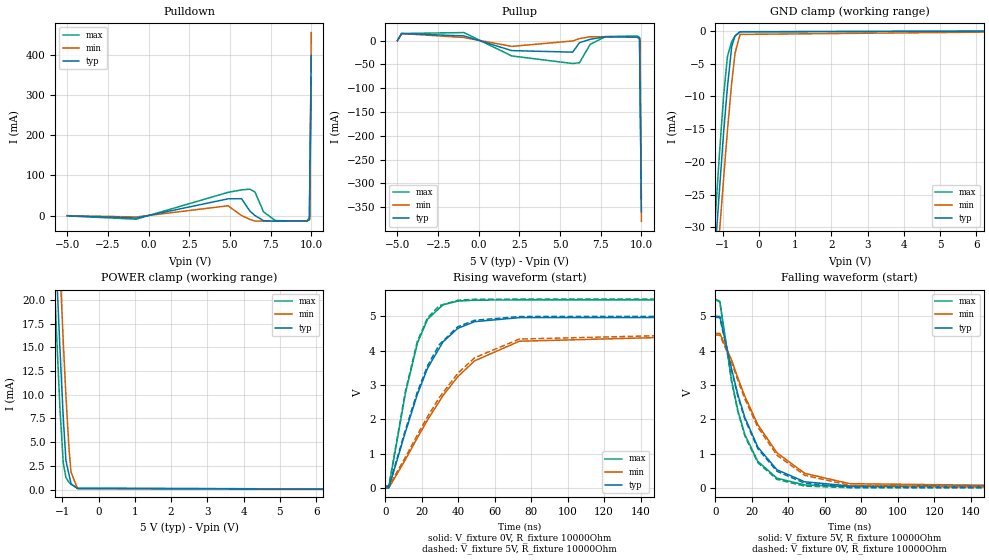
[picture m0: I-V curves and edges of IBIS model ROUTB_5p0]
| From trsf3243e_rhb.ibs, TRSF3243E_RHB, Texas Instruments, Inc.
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[Model]   ROUTB_5p0
Model_type   3-state
Polarity   Inverting
Vmeas = 2.5
Vref = 0
Cref = 150pF
Rref = 3000
|variable   typ   min   max
C_comp   1.38pF   1.30pF   1.43pF
|C_pullup   1.31pF   1.23pF   1.37pF
|C_pulldown   1.78pF   1.74pF   1.85pF
[Voltage Range]   5   4.5   5.5
[Temperature Range]   27   110   -40
[Pullup Reference]   5   4.5   5.5
[Pulldown Reference]   0   0   0
[Power Clamp Reference]   5   4.5   5.5
[GND Clamp Reference]   0   0   0
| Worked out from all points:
|   slope of the pulldown table from 0 to 0.75 V, typ, clamps not added: 91.3 ohm
|   slope of the pullup table from 0 to 0.75 V, typ, clamps not added: 81.9 ohm
|   GND clamp passes 1 mA (typ) near -0.68 V on its own axis
|   POWER clamp passes 1 mA (typ) near -0.78 V on its own axis
|   falling waveform, V_fixture 5V, R_fixture 10000Ohm: 20-80 % time 18.4ns typ, 25.7ns min, 14.3ns max; typ from 5 V to 0.039 V
|   rising waveform, V_fixture 0V, R_fixture 10000Ohm: 20-80 % time 20.4ns typ, 34.1ns min, 13.2ns max; typ from 0 V to 4.97 V
|   rising waveform, V_fixture 5V, R_fixture 10000Ohm: 20-80 % time 20.1ns typ, 33.3ns min, 13.1ns max; typ from 0.039 V to 5 V
|   falling waveform, V_fixture 0V, R_fixture 10000Ohm: 20-80 % time 18.3ns typ, 25.4ns min, 14.3ns max; typ from 4.97 V to 0 V
[Pulldown]
|   Voltage   I(typ)   I(min)   I(max)
-5V       -780.8uA   -278.4uA   -898.2uA
-764.5mV  -6.348mA   -3.623mA   -9.147mA
4.882V    41.67mA    24.34mA    57.85mA
5.716V    42.05mA    48.26uA    64mA
6.228V    11.15mA    -9.654mA   65.9mA
6.544V    -20.3uA    -13.84mA   58.36mA
7.073V    -13.01mA   -14.06mA   8.908mA
7.792V    -13.95mA   -14.24mA   -12.54mA
9.735V    -13.05mA   -13.19mA   -14.43mA
9.886V    -10.99mA   -9.056mA   -5.798mA
9.915V    91.58mA    -8.283mA   81.7mA
10V       399.8mA    457.1mA    344.6mA
[GND Clamp]
|   Voltage   I(typ)   I(min)   I(max)
-5V       -355.6mA   -336.7mA   -374.9mA
-1.338V   -44.36mA   -49.37mA   -40.19mA
-1.205V   -33.57mA   -39.45mA   -28.67mA
-1.163V   -30.18mA   -36.27mA   -25.03mA
-1.135V   -27.99mA   -34.25mA   -22.74mA
-1.089V   -24.36mA   -30.81mA   -18.83mA
-973.6mV  -15.53mA   -22.56mA   -9.873mA
-867.4mV  -8.559mA   -15.17mA   -3.914mA
-750.6mV  -2.375mA   -7.945mA   -1.647mA
-658.6mV  -799.2uA   -3.415mA   -780.7uA
-521.1mV  -136.1uA   -548.3uA   -156.3uA
10V       0A         0A         0A
[Pullup]
|   Voltage   I(typ)   I(min)   I(max)
-5V       98.14uA    69.08uA    126.7uA
-4.742V   15mA       14.94mA    15.05mA
-911.9mV  9.999mA    6.652mA    17.02mA
2.029V    -20.9mA    -12.03mA   -32.14mA
5.777V    -24.16mA   -600.8uA   -48.04mA
6.193V    -4.317mA   4.357mA    -46.36mA
6.853V    2.92mA     8.214mA    -7.749mA
7.792V    8.278mA    8.328mA    8.582mA
9.735V    7.295mA    7.355mA    9.879mA
9.885V    5.533mA    4.087mA    6.708mA
9.915V    -85.71mA   3.431mA    -81.8mA
10V       -359.8mA   -379.7mA   -332.8mA
[POWER Clamp]
|   Voltage   I(typ)   I(min)   I(max)
-5V       399.5mA    407.3mA    393.9mA
-1.338V   39.38mA    48.14mA    32.77mA
-1.205V   27.08mA    35.95mA    20.57mA
-1.157V   22.77mA    31.52mA    16.31mA
-1.082V   16.27mA    24.77mA    9.909mA
-1.06V    14.41mA    22.89mA    8.13mA
-973.6mV  7.547mA    15.58mA    2.804mA
-900.9mV  3.072mA    9.867mA    1.276mA
-815.6mV  1.585mA    4.271mA    761.5uA
-759.7mV  610.8uA    1.847mA    554.6uA
-582.8mV  106.4uA    113.1uA    169.6uA
10V       0A         0A         0A
[Ramp]
R_load = 10000
|   typ   min   max
dV/dt_r   2.98109/2.04131e-08   2.67144/3.41326e-08   3.2869/1.32517e-08
dV/dt_f   2.97654/1.8391e-08   2.67255/2.57068e-08   3.27911/1.43282e-08
[Falling Waveform]
V_fixture = 5V
V_fixture_min = 4.5V
V_fixture_max = 5.5V
R_fixture = 10000Ohm
C_fixture = 0F
|   Time   V(typ)   V(min)   V(max)
0s        5V         4.5V       5.5V
2.43ns    4.997V     4.503V     5.439V
8.848ns   3.473V     3.727V     3.136V
12.4ns    2.703V     3.192V     2.237V
16.22ns   2.042V     2.658V     1.543V
23.24ns   1.19V      1.846V     773.4mV
33.78ns   525.1mV    1.019V     281.3mV
49.01ns   177.2mV    422.9mV    84.63mV
73.58ns   55.02mV    121.5mV    38.23mV
200ns     39.1mV     45.76mV    34.81mV
[Rising Waveform]
V_fixture = 0V
V_fixture_min = 0V
V_fixture_max = 0V
R_fixture = 10000Ohm
C_fixture = 0F
|   Time   V(typ)   V(min)   V(max)
0s        -139.6nV   -88.58nV   -98.3nV
1.973ns   -908.4uV   -22.57uV   26.62mV
11.12ns   1.635V     826.1mV    2.769V
17.61ns   2.721V     1.457V     4.216V
23.24ns   3.49V      1.981V     4.917V
31.7ns    4.255V     2.69V      5.336V
39.76ns   4.646V     3.238V     5.442V
49.01ns   4.844V     3.701V     5.47V
73.58ns   4.96V      4.273V     5.478V
200ns     4.968V     4.452V     5.478V
[Rising Waveform]
V_fixture = 5V
V_fixture_min = 4.5V
V_fixture_max = 5.5V
R_fixture = 10000Ohm
C_fixture = 0F
|   Time   V(typ)   V(min)   V(max)
0s        39.1mV     45.83mV    34.81mV
1.973ns   38.21mV    45.8mV     61.49mV
11.12ns   1.699V     895.1mV    2.828V
17.61ns   2.796V     1.543V     4.27V
23.24ns   3.564V     2.077V     4.959V
29.68ns   4.177V     2.635V     5.31V
39.76ns   4.695V     3.338V     5.466V
49.01ns   4.884V     3.791V     5.494V
73.58ns   4.993V     4.336V     5.5V
200ns     5V         4.5V       5.5V
[Falling Waveform]
|Gnd
V_fixture = 0V
V_fixture_min = 0V
V_fixture_max = 0V
R_fixture = 10000Ohm
C_fixture = 0F
|   Time   V(typ)   V(min)   V(max)
0s        4.968V     4.452V     5.478V
2.405ns   4.966V     4.454V     5.421V
8.848ns   3.426V     3.662V     3.101V
12.4ns    2.654V     3.121V     2.2V
16.22ns   1.992V     2.583V     1.505V
23.24ns   1.142V     1.771V     736.3mV
33.78ns   480.8mV    951.5mV    245.3mV
49.01ns   136.1mV    366.1mV    52.06mV
73.58ns   15.59mV    72.69mV    3.382mV
200ns     -5.346uV   -64.64uV   4.327uV
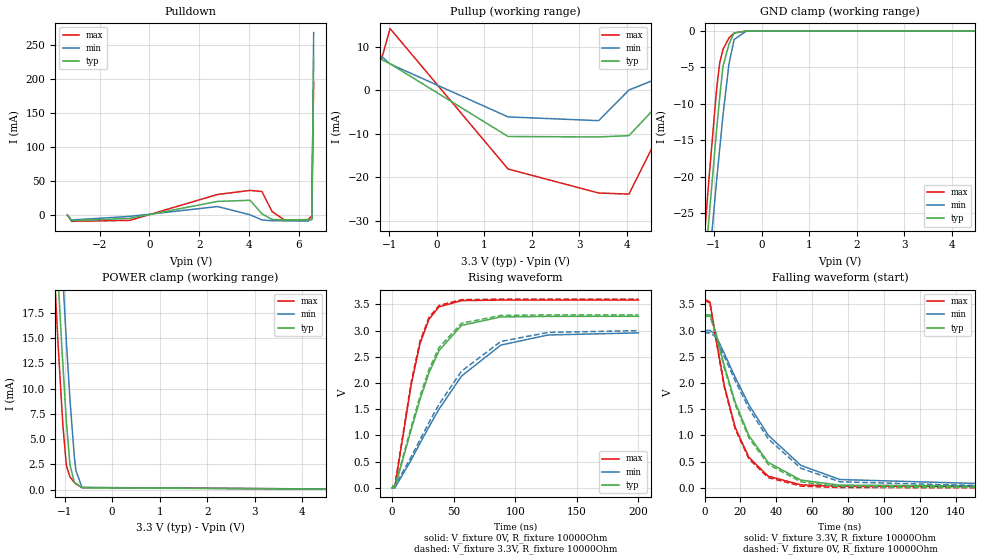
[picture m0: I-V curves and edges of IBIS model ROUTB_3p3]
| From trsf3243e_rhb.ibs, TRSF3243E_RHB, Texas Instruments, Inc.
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[Model]   ROUTB_3p3
Model_type   3-state
Polarity   Inverting
Vmeas = 1.65
Vref = 0
Cref = 150pF
Rref = 3000
|variable   typ   min   max
C_comp   1.47pF   1.38pF   1.52pF
|C_pullup   1.38pF   1.27pF   1.45pF
|C_pulldown   1.80pF   1.75pF   1.86pF
[Voltage Range]   3.3   3   3.6
[Temperature Range]   27   110   -40
[Pullup Reference]   3.3   3   3.6
[Pulldown Reference]   0   0   0
[Power Clamp Reference]   3.3   3   3.6
[GND Clamp Reference]   0   0   0
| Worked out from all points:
|   slope of the pulldown table from 0 to 0.495 V, typ, clamps not added: 119 ohm
|   slope of the pullup table from 0 to 0.495 V, typ, clamps not added: 136 ohm
|   GND clamp passes 1 mA (typ) near -0.65 V on its own axis
|   POWER clamp passes 1 mA (typ) near -0.82 V on its own axis
|   falling waveform, V_fixture 3.3V, R_fixture 10000Ohm: 20-80 % time 21.7ns typ, 32.6ns min, 15.9ns max; typ from 3.3 V to 0.029 V
|   rising waveform, V_fixture 0V, R_fixture 10000Ohm: 20-80 % time 27.9ns typ, 48.7ns min, 17.3ns max; typ from 0 V to 3.27 V
|   rising waveform, V_fixture 3.3V, R_fixture 10000Ohm: 20-80 % time 27.3ns typ, 47.1ns min, 17ns max; typ from 0.029 V to 3.3 V
|   falling waveform, V_fixture 0V, R_fixture 10000Ohm: 20-80 % time 21.6ns typ, 32.1ns min, 15.9ns max; typ from 3.27 V to 0 V
[Pulldown]
|   Voltage   I(typ)   I(min)   I(max)
-3.3V     -787.1uA   -298.2uA   -879.3uA
-3.13V    -9.259mA   -8.11mA    -9.971mA
-788.7mV  -5.612mA   -2.71mA    -8.598mA
2.735V    19.39mA    11.81mA    29.64mA
4.042V    21.08mA    -312.1uA   35.66mA
4.523V    1.033mA    -7.969mA   33.99mA
4.925V    -7.207mA   -9.102mA   4.57mA
5.433V    -7.855mA   -9.28mA    -8.328mA
6.366V    -7.517mA   -9.606mA   -7.618mA
6.522V    -7.461mA   -6.718mA   -2.416mA
6.532V    24.7mA     -6.523mA   24.29mA
6.6V      231.2mA    268.8mA    195.7mA
[GND Clamp]
|   Voltage   I(typ)   I(min)   I(max)
-3.3V     -210.1mA   -202.3mA   -218.6mA
-1.348V   -45.17mA   -50.25mA   -41.18mA
-1.208V   -33.83mA   -39.74mA   -28.91mA
-1.175V   -31.12mA   -37.23mA   -26.05mA
-1.107V   -25.78mA   -32.11mA   -20.34mA
-942mV    -13.28mA   -20.29mA   -7.725mA
-879.8mV  -9.08mA    -16.12mA   -4.389mA
-811.2mV  -4.875mA   -11.57mA   -2.536mA
-686.3mV  -1.833mA   -4.566mA   -987.9uA
-577mV    -278.2uA   -1.197mA   -309.3uA
-315.2mV  -33.26uA   -7.242uA   -7.414uA
6.6V      0A         0A         0A
[Pullup]
|   Voltage   I(typ)   I(min)   I(max)
-3.3V     131.1uA    87.96uA    178.1uA
-3.13V    9.92mA     9.846mA    9.995mA
-1.163V   7.022mA    7.761mA    7.124mA
-984.1mV  6.064mA    6.007mA    14.15mA
1.499V    -10.66mA   -6.155mA   -18.13mA
3.404V    -10.76mA   -7.017mA   -23.64mA
4.042V    -10.46mA   18.97uA    -23.9mA
5.433V    5.648mA    6.097mA    6.407mA
6.366V    4.745mA    6.255mA    5.441mA
6.52V     4.596mA    3.972mA    5.281mA
6.532V    -24.61mA   3.786mA    -25.75mA
6.6V      -212.1mA   -227.5mA   -193.1mA
[POWER Clamp]
|   Voltage   I(typ)   I(min)   I(max)
-3.3V     230.9mA    239.1mA    225mA
-1.254V   31.57mA    40.43mA    25.24mA
-1.175V   24.31mA    33.19mA    17.85mA
-1.131V   20.41mA    29.18mA    13.95mA
-1.06V    14.27mA    22.94mA    8.245mA
-1.035V   12.33mA    20.8mA     6.311mA
-961.9mV  6.695mA    14.63mA    2.369mA
-887.3mV  2.484mA    8.947mA    1.267mA
-795.8mV  739.7uA    3.272mA    699uA
-760mV    616.4uA    1.855mA    553.7uA
-633.3mV  180.3uA    217uA      201.5uA
6.6V      0A         0A         0A
[Ramp]
R_load = 10000
|   typ   min   max
dV/dt_r   1.96363/2.79356e-08   1.77363/4.8671e-08   2.14915/1.72734e-08
dV/dt_f   1.96255/2.17589e-08   1.77823/3.26253e-08   2.14523/1.59509e-08
[Falling Waveform]
V_fixture = 3.3V
V_fixture_min = 3V
V_fixture_max = 3.6V
R_fixture = 10000Ohm
C_fixture = 0F
|   Time   V(typ)   V(min)   V(max)
0s        3.3V       3V         3.6V
3.021ns   3.301V     3.001V     3.545V
5.942ns   3.011V     2.932V     2.932V
11.03ns   2.329V     2.563V     1.951V
17.15ns   1.628V     2.106V     1.149V
24.77ns   996.4mV    1.584V     580.2mV
35.47ns   486.9mV    1.005V     223.6mV
53.77ns   147.3mV    427.5mV    58.24mV
75.54ns   51.26mV    158.8mV    29.98mV
200ns     29.08mV    36.28mV    24.61mV
[Rising Waveform]
V_fixture = 0V
V_fixture_min = 0V
V_fixture_max = 0V
R_fixture = 10000Ohm
C_fixture = 0F
|   Time   V(typ)   V(min)   V(max)
0s        -26.61nV   -137.3nV   -168.2nV
2.244ns   -755.5uV   -551.8uV   17.25mV
15.45ns   1.105V     530.2mV    1.962V
22.62ns   1.682V     849mV      2.75V
29.93ns   2.191V     1.164V     3.216V
38.16ns   2.62V      1.503V     3.453V
56.37ns   3.099V     2.132V     3.571V
88.29ns   3.26V      2.723V     3.582V
126.7ns   3.271V     2.916V     3.582V
200ns     3.273V     2.956V     3.582V
[Rising Waveform]
V_fixture = 3.3V
V_fixture_min = 3V
V_fixture_max = 3.6V
R_fixture = 10000Ohm
C_fixture = 0F
|   Time   V(typ)   V(min)   V(max)
0s        29.11mV    36.29mV    24.61mV
2.244ns   28.38mV    35.8mV     41.95mV
15.45ns   1.158V     588.3mV    2.01V
22.62ns   1.745V     918.4mV    2.795V
29.93ns   2.256V     1.246V     3.251V
38.16ns   2.679V     1.595V     3.479V
56.37ns   3.14V      2.227V     3.59V
88.29ns   3.289V     2.792V     3.6V
126.7ns   3.299V     2.965V     3.6V
200ns     3.3V       2.999V     3.6V
[Falling Waveform]
|Gnd
V_fixture = 0V
V_fixture_min = 0V
V_fixture_max = 0V
R_fixture = 10000Ohm
C_fixture = 0F
|   Time   V(typ)   V(min)   V(max)
0s        3.273V     2.957V     3.582V
3.021ns   3.272V     2.957V     3.524V
5.742ns   3.003V     2.895V     2.95V
11.03ns   2.287V     2.505V     1.922V
17.15ns   1.583V     2.04V      1.119V
24.77ns   953.9mV    1.513V     551.9mV
35.47ns   449.3mV    937.7mV    197.1mV
53.77ns   115.2mV    373.2mV    33.18mV
75.54ns   21.42mV    115.2mV    5.28mV
200ns     -27.36uV   -10.49uV   4.974uV
